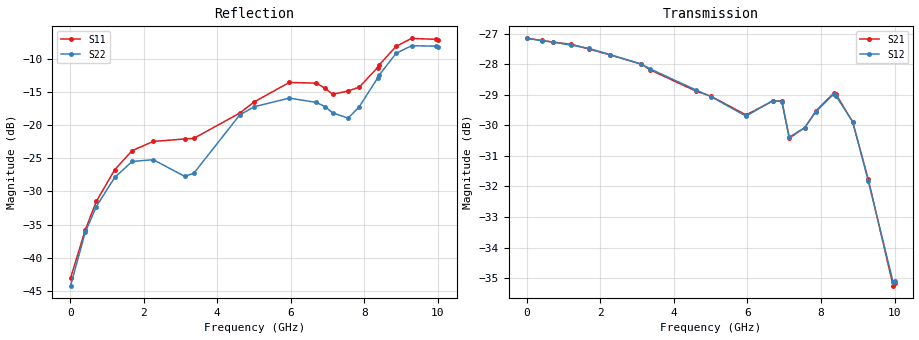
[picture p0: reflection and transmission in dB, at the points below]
! Device ID: PE43704
! Dir: z:\PE43704\PE43704_Char_1_20130516\PE43704\AMB\3p400V\26p25dB
! Serial: 14
! Insertion: A
! Impedance: 50 ohm
! Temp: Amb
! VDD: 3.400V
! Attenuation Step: 26.25dB
! IDD: 1.140511e-01mA
#  Hz  S  RI  R  50
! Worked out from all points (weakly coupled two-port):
!   401 points, 10 MHz to 10.01 GHz, reference 50 ohm
!   highest |S21| = -27.15 dB at 10 MHz (marker M1); lowest = -35.3 dB at 9.96 GHz (marker M2)
!   lowest |S11| = -43.1 dB at 10 MHz (marker M3), VSWR 1.01, Z = 50.7 + j0.0414 ohm
!   |S11| at or under -10 dB: start of sweep to 8.532 GHz
!   |S22| runs from -44.2 to -7.8 dB; largest |S21 - S12| = 0.00071
!   S11 on the Smith chart (normalised r, x): 10 MHz: 1.01, +0.00; 4.61 GHz: 0.80, +0.08; 8.41 GHz: 0.78, +0.47; 9.285 GHz: 0.52, +0.55; 10.01 GHz: 0.45, +0.33
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1e7  0.00702 0.000408  0.0439 -0.000127  0.0439 -6.84e-05  0.00615 0.00035
4.1e8  0.000794 0.0162  0.0433 -0.00466  0.0433 -0.00448  0.000817 0.0156
7.1e8  -0.0121 0.0237  0.0426 -0.00768  0.0426 -0.00765  -0.0108 0.0218
1.21e9  -0.0406 0.0218  0.041 -0.0127  0.0409 -0.0126  -0.0362 0.0179
1.685e9  -0.0638 0.00774  0.0386 -0.017  0.0387 -0.017  -0.0532 0.00245
2.26e9  -0.0746 -0.0108  0.0352 -0.0215  0.0352 -0.0216  -0.0534 -0.0126
3.11e9  -0.0772 -0.0153  0.0292 -0.0271  0.0293 -0.027  -0.041 -0.00363
3.36e9  -0.079 -0.00896  0.027 -0.0281  0.0272 -0.0281  -0.043 0.00527
4.61e9  -0.1116 0.0523  0.0177 -0.0313  0.018 -0.0313  -0.1046 0.0576
5.01e9  -0.1308 0.0738  0.0159 -0.0315  0.0158 -0.0315  -0.1256 0.057
5.96e9  -0.181 0.1064  0.00948 -0.0315  0.0096 -0.0313  -0.1504 0.0543
6.685e9  -0.1812 0.1012  0.00661 -0.034  0.00655 -0.0341  -0.1389 0.0529
6.935e9  -0.1633 0.0969  0.00235 -0.0346  0.00247 -0.0345  -0.1239 0.0605
7.135e9  -0.1479 0.0851  0.00153 -0.0301  0.00165 -0.0302  -0.1041 0.0672
7.56e9  -0.1226 0.1337  0.00171 -0.0313  0.00193 -0.0313  -0.0682 0.0901
7.86e9  -0.0859 0.173  0.000833 -0.0334  0.000873 -0.0333  -0.0588 0.1243
8.36e9  -0.0501 0.2675  -0.00742 -0.035  -0.00729 -0.0349  -0.0731 0.2146
8.41e9  -0.0509 0.281  -0.00812 -0.0346  -0.00838 -0.0343  -0.0795 0.2262
8.86e9  -0.0894 0.3822  -0.015 -0.0283  -0.0149 -0.0284  -0.1383 0.3189
9.285e9  -0.1655 0.4199  -0.0147 -0.0212  -0.0147 -0.021  -0.2185 0.3321
9.96e9  -0.3057 0.3213  -0.00443 -0.0167  -0.00462 -0.0169  -0.3488 0.1833
1.001e10  -0.3134 0.3026  -0.00343 -0.0171  -0.00362 -0.0172  -0.3534 0.1629
